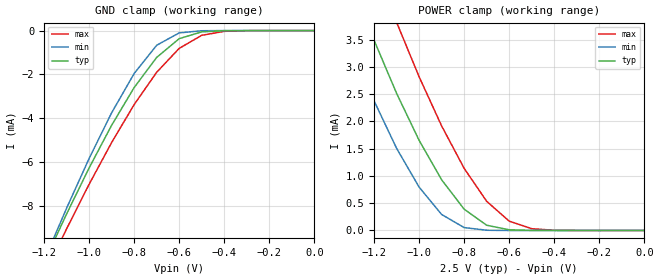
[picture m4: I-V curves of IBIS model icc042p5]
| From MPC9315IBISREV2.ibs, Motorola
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|This is a Model of an Input with a 25,000 ohm Pull_down at 2.5V
[Model]   icc042p5
Model_type   Input
Vmeas=1.25
Vinl=0.7
Vinh=1.7
| Variable   typ   min   max
C_comp   5p   5p   5p
[Temperature Range]   27.00   100.00   -45.00
[Power Clamp Reference]   2.50V   2.25V   2.75V
[Gnd Clamp Reference]   0.000V   0.000V   0.000V
[Voltage Range]   2.50V   2.25V   2.75V
[Pulldown Reference]   0.000V   0.000V   0.000V
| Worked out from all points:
|   GND clamp passes 1 mA (typ) near -0.67 V on its own axis
|   POWER clamp passes 1 mA (typ) near -0.91 V on its own axis
[GND_clamp]
| voltage   I(typ)   I(min)   I(max)
-2.5V     -42.32mA   -44.12mA   -41.95mA
-1.2V     -10.57mA   -10.49mA   -11.17mA
-1.1V     -8.363mA   -8.101mA   -9.042mA
-1V       -6.263mA   -5.833mA   -7.009mA
-900mV    -4.318mA   -3.748mA   -5.104mA
-800mV    -2.598mA   -1.958mA   -3.374mA
-700mV    -1.223mA   -669.1uA   -1.901mA
-600mV    -367.4uA   -105.4uA   -811uA
-500mV    -58.52uA   -8.126uA   -215.8uA
-400mV    -5.383uA   -283nA     -33.88uA
1.08fV    -5.997pA   -2.5pA     -3.129nA
[POWER_clamp]
| voltage   I(typ)  I(min)  I(max)
-2.5V     20.92mA    19.68mA    22.84mA
-1.4V     5.706mA    4.479mA    7.266mA
-1.3V     4.561mA    3.379mA    6.054mA
-1.2V     3.493mA    2.381mA    4.903mA
-1.1V     2.518mA    1.509mA    3.822mA
-1V       1.655mA    796.6uA    2.822mA
-900mV    930.3uA    293.6uA    1.919mA
-800mV    391.2uA    53.28uA    1.14mA
-700mV    96.35uA    4.13uA     535.5uA
-600mV    12.19uA    177.5nA    171.1uA
-500mV    1.038uA    4.826nA    32.15uA
1.08fV    126pA      102.5pA    3.439nA
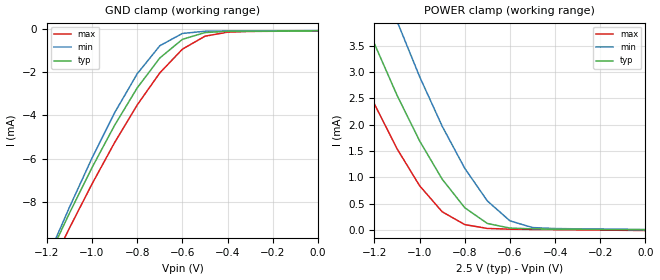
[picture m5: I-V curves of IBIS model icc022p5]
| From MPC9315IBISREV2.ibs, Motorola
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|This is a Model of an Input with a 25,000 ohm Pull_up at 2.5V
[Model]   icc022p5
Model_type   Input
Vmeas=1.25
Vinl=.7
Vinh=1.7
| Variable   typ   min   max
C_comp   5p   5p   5p
[Temperature Range]   27.00   100.00   -45.00
[Power Clamp Reference]   2.50V   2.25V   2.75V
[Gnd Clamp Reference]   0.000V   0.000V   0.000V
[Voltage Range]   2.50V   2.25V   2.75V
[Pulldown Reference]   0.000V   0.000V   0.000V
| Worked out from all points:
|   GND clamp passes 1 mA (typ) near -0.66 V on its own axis
|   POWER clamp passes 1 mA (typ) near -0.90 V on its own axis
[GND_clamp]
| voltage   I(typ)   I(min)   I(max)
-2.5V     -42.51mA   -44.31mA   -42.15mA
-1.2V     -10.71mA   -10.62mA   -11.32mA
-1.1V     -8.502mA   -8.23mA    -9.191mA
-1V       -6.399mA   -5.958mA   -7.155mA
-900mV    -4.45mA    -3.87mA    -5.246mA
-800mV    -2.726mA   -2.077mA   -3.513mA
-700mV    -1.348mA   -784.8uA   -2.036mA
-600mV    -489.4uA   -218uA     -942.6uA
-500mV    -177.2uA   -117uA     -344uA
-400mV    -120.2uA   -105.2uA   -158.5uA
1.08fV    -99.01uA   -89.1uA    -108.9uA
[POWER_clamp]
| voltage   I(typ)  I(min)  I(max)
-2.5V     21.02mA    23.53mA    19.16mA
-1.4V     5.76mA     7.621mA    4.398mA
-1.3V     4.611mA    6.339mA    3.352mA
-1.2V     3.54mA     5.117mA    2.394mA
-1.1V     2.561mA    3.97mA     1.545mA
-1V       1.694mA    2.915mA    841.2uA
-900mV    965.7uA    1.972mA    346.2uA
-800mV    422.8uA    1.172mA    102.4uA
-700mV    124uA      552.3uA    28.88uA
-600mV    35.95uA    173.7uA    15.08uA
-500mV    20.84uA    45.83uA    10.02uA
1.08fV    26.02pA    9.901uA    -9.897uA
